VERSION 5.7 ;
BUSBITCHARS "[]" ;
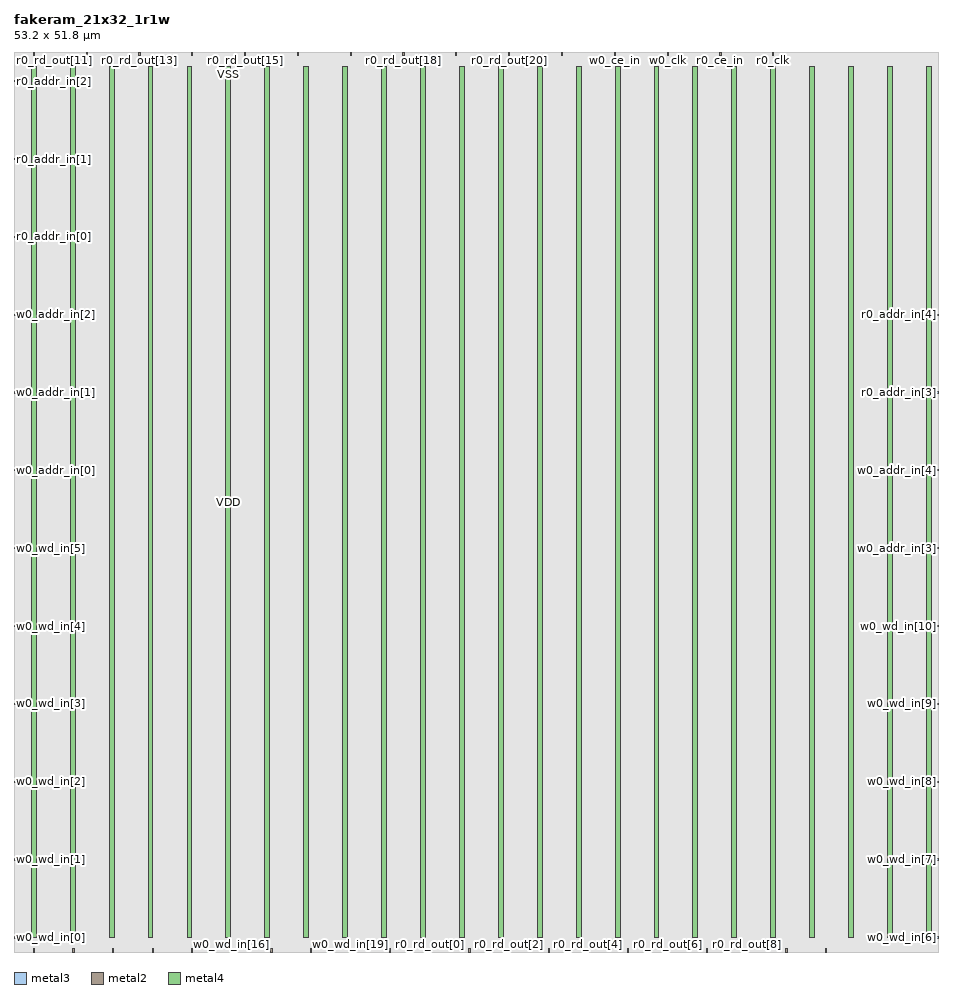
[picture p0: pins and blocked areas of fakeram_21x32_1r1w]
MACRO fakeram_21x32_1r1w
  FOREIGN fakeram_21x32_1r1w 0 0 ;
  SYMMETRY X Y R90 ;
  SIZE 53.200 BY 51.800 ;
  CLASS BLOCK ;
  PIN w0_wd_in[0]
    DIRECTION INPUT ;
    USE SIGNAL ;
    SHAPE ABUTMENT ;
    PORT
      LAYER metal3 ;
      RECT 0.000 0.805 0.210 0.875 ;
    END
  END w0_wd_in[0]
  PIN w0_wd_in[1]
    DIRECTION INPUT ;
    USE SIGNAL ;
    SHAPE ABUTMENT ;
    PORT
      LAYER metal3 ;
      RECT 0.000 5.285 0.210 5.355 ;
    END
  END w0_wd_in[1]
  PIN w0_wd_in[2]
    DIRECTION INPUT ;
    USE SIGNAL ;
    SHAPE ABUTMENT ;
    PORT
      LAYER metal3 ;
      RECT 0.000 9.765 0.210 9.835 ;
    END
  END w0_wd_in[2]
  PIN w0_wd_in[3]
    DIRECTION INPUT ;
    USE SIGNAL ;
    SHAPE ABUTMENT ;
    PORT
      LAYER metal3 ;
      RECT 0.000 14.245 0.210 14.315 ;
    END
  END w0_wd_in[3]
  PIN w0_wd_in[4]
    DIRECTION INPUT ;
    USE SIGNAL ;
    SHAPE ABUTMENT ;
    PORT
      LAYER metal3 ;
      RECT 0.000 18.725 0.210 18.795 ;
    END
  END w0_wd_in[4]
  PIN w0_wd_in[5]
    DIRECTION INPUT ;
    USE SIGNAL ;
    SHAPE ABUTMENT ;
    PORT
      LAYER metal3 ;
      RECT 0.000 23.205 0.210 23.275 ;
    END
  END w0_wd_in[5]
  PIN w0_wd_in[6]
    DIRECTION INPUT ;
    USE SIGNAL ;
    SHAPE ABUTMENT ;
    PORT
      LAYER metal3 ;
      RECT 52.990 0.805 53.200 0.875 ;
    END
  END w0_wd_in[6]
  PIN w0_wd_in[7]
    DIRECTION INPUT ;
    USE SIGNAL ;
    SHAPE ABUTMENT ;
    PORT
      LAYER metal3 ;
      RECT 52.990 5.285 53.200 5.355 ;
    END
  END w0_wd_in[7]
  PIN w0_wd_in[8]
    DIRECTION INPUT ;
    USE SIGNAL ;
    SHAPE ABUTMENT ;
    PORT
      LAYER metal3 ;
      RECT 52.990 9.765 53.200 9.835 ;
    END
  END w0_wd_in[8]
  PIN w0_wd_in[9]
    DIRECTION INPUT ;
    USE SIGNAL ;
    SHAPE ABUTMENT ;
    PORT
      LAYER metal3 ;
      RECT 52.990 14.245 53.200 14.315 ;
    END
  END w0_wd_in[9]
  PIN w0_wd_in[10]
    DIRECTION INPUT ;
    USE SIGNAL ;
    SHAPE ABUTMENT ;
    PORT
      LAYER metal3 ;
      RECT 52.990 18.725 53.200 18.795 ;
    END
  END w0_wd_in[10]
  PIN w0_wd_in[11]
    DIRECTION INPUT ;
    USE SIGNAL ;
    SHAPE ABUTMENT ;
    PORT
      LAYER metal2 ;
      RECT 1.105 0.000 1.175 0.210 ;
    END
  END w0_wd_in[11]
  PIN w0_wd_in[12]
    DIRECTION INPUT ;
    USE SIGNAL ;
    SHAPE ABUTMENT ;
    PORT
      LAYER metal2 ;
      RECT 3.385 0.000 3.455 0.210 ;
    END
  END w0_wd_in[12]
  PIN w0_wd_in[13]
    DIRECTION INPUT ;
    USE SIGNAL ;
    SHAPE ABUTMENT ;
    PORT
      LAYER metal2 ;
      RECT 5.665 0.000 5.735 0.210 ;
    END
  END w0_wd_in[13]
  PIN w0_wd_in[14]
    DIRECTION INPUT ;
    USE SIGNAL ;
    SHAPE ABUTMENT ;
    PORT
      LAYER metal2 ;
      RECT 7.945 0.000 8.015 0.210 ;
    END
  END w0_wd_in[14]
  PIN w0_wd_in[15]
    DIRECTION INPUT ;
    USE SIGNAL ;
    SHAPE ABUTMENT ;
    PORT
      LAYER metal2 ;
      RECT 10.225 0.000 10.295 0.210 ;
    END
  END w0_wd_in[15]
  PIN w0_wd_in[16]
    DIRECTION INPUT ;
    USE SIGNAL ;
    SHAPE ABUTMENT ;
    PORT
      LAYER metal2 ;
      RECT 12.505 0.000 12.575 0.210 ;
    END
  END w0_wd_in[16]
  PIN w0_wd_in[17]
    DIRECTION INPUT ;
    USE SIGNAL ;
    SHAPE ABUTMENT ;
    PORT
      LAYER metal2 ;
      RECT 14.785 0.000 14.855 0.210 ;
    END
  END w0_wd_in[17]
  PIN w0_wd_in[18]
    DIRECTION INPUT ;
    USE SIGNAL ;
    SHAPE ABUTMENT ;
    PORT
      LAYER metal2 ;
      RECT 17.065 0.000 17.135 0.210 ;
    END
  END w0_wd_in[18]
  PIN w0_wd_in[19]
    DIRECTION INPUT ;
    USE SIGNAL ;
    SHAPE ABUTMENT ;
    PORT
      LAYER metal2 ;
      RECT 19.345 0.000 19.415 0.210 ;
    END
  END w0_wd_in[19]
  PIN w0_wd_in[20]
    DIRECTION INPUT ;
    USE SIGNAL ;
    SHAPE ABUTMENT ;
    PORT
      LAYER metal2 ;
      RECT 21.625 0.000 21.695 0.210 ;
    END
  END w0_wd_in[20]
  PIN r0_rd_out[0]
    DIRECTION OUTPUT ;
    USE SIGNAL ;
    SHAPE ABUTMENT ;
    PORT
      LAYER metal2 ;
      RECT 23.905 0.000 23.975 0.210 ;
    END
  END r0_rd_out[0]
  PIN r0_rd_out[1]
    DIRECTION OUTPUT ;
    USE SIGNAL ;
    SHAPE ABUTMENT ;
    PORT
      LAYER metal2 ;
      RECT 26.185 0.000 26.255 0.210 ;
    END
  END r0_rd_out[1]
  PIN r0_rd_out[2]
    DIRECTION OUTPUT ;
    USE SIGNAL ;
    SHAPE ABUTMENT ;
    PORT
      LAYER metal2 ;
      RECT 28.465 0.000 28.535 0.210 ;
    END
  END r0_rd_out[2]
  PIN r0_rd_out[3]
    DIRECTION OUTPUT ;
    USE SIGNAL ;
    SHAPE ABUTMENT ;
    PORT
      LAYER metal2 ;
      RECT 30.745 0.000 30.815 0.210 ;
    END
  END r0_rd_out[3]
  PIN r0_rd_out[4]
    DIRECTION OUTPUT ;
    USE SIGNAL ;
    SHAPE ABUTMENT ;
    PORT
      LAYER metal2 ;
      RECT 33.025 0.000 33.095 0.210 ;
    END
  END r0_rd_out[4]
  PIN r0_rd_out[5]
    DIRECTION OUTPUT ;
    USE SIGNAL ;
    SHAPE ABUTMENT ;
    PORT
      LAYER metal2 ;
      RECT 35.305 0.000 35.375 0.210 ;
    END
  END r0_rd_out[5]
  PIN r0_rd_out[6]
    DIRECTION OUTPUT ;
    USE SIGNAL ;
    SHAPE ABUTMENT ;
    PORT
      LAYER metal2 ;
      RECT 37.585 0.000 37.655 0.210 ;
    END
  END r0_rd_out[6]
  PIN r0_rd_out[7]
    DIRECTION OUTPUT ;
    USE SIGNAL ;
    SHAPE ABUTMENT ;
    PORT
      LAYER metal2 ;
      RECT 39.865 0.000 39.935 0.210 ;
    END
  END r0_rd_out[7]
  PIN r0_rd_out[8]
    DIRECTION OUTPUT ;
    USE SIGNAL ;
    SHAPE ABUTMENT ;
    PORT
      LAYER metal2 ;
      RECT 42.145 0.000 42.215 0.210 ;
    END
  END r0_rd_out[8]
  PIN r0_rd_out[9]
    DIRECTION OUTPUT ;
    USE SIGNAL ;
    SHAPE ABUTMENT ;
    PORT
      LAYER metal2 ;
      RECT 44.425 0.000 44.495 0.210 ;
    END
  END r0_rd_out[9]
  PIN r0_rd_out[10]
    DIRECTION OUTPUT ;
    USE SIGNAL ;
    SHAPE ABUTMENT ;
    PORT
      LAYER metal2 ;
      RECT 46.705 0.000 46.775 0.210 ;
    END
  END r0_rd_out[10]
  PIN r0_rd_out[11]
    DIRECTION OUTPUT ;
    USE SIGNAL ;
    SHAPE ABUTMENT ;
    PORT
      LAYER metal2 ;
      RECT 1.105 51.590 1.175 51.800 ;
    END
  END r0_rd_out[11]
  PIN r0_rd_out[12]
    DIRECTION OUTPUT ;
    USE SIGNAL ;
    SHAPE ABUTMENT ;
    PORT
      LAYER metal2 ;
      RECT 4.145 51.590 4.215 51.800 ;
    END
  END r0_rd_out[12]
  PIN r0_rd_out[13]
    DIRECTION OUTPUT ;
    USE SIGNAL ;
    SHAPE ABUTMENT ;
    PORT
      LAYER metal2 ;
      RECT 7.185 51.590 7.255 51.800 ;
    END
  END r0_rd_out[13]
  PIN r0_rd_out[14]
    DIRECTION OUTPUT ;
    USE SIGNAL ;
    SHAPE ABUTMENT ;
    PORT
      LAYER metal2 ;
      RECT 10.225 51.590 10.295 51.800 ;
    END
  END r0_rd_out[14]
  PIN r0_rd_out[15]
    DIRECTION OUTPUT ;
    USE SIGNAL ;
    SHAPE ABUTMENT ;
    PORT
      LAYER metal2 ;
      RECT 13.265 51.590 13.335 51.800 ;
    END
  END r0_rd_out[15]
  PIN r0_rd_out[16]
    DIRECTION OUTPUT ;
    USE SIGNAL ;
    SHAPE ABUTMENT ;
    PORT
      LAYER metal2 ;
      RECT 16.305 51.590 16.375 51.800 ;
    END
  END r0_rd_out[16]
  PIN r0_rd_out[17]
    DIRECTION OUTPUT ;
    USE SIGNAL ;
    SHAPE ABUTMENT ;
    PORT
      LAYER metal2 ;
      RECT 19.345 51.590 19.415 51.800 ;
    END
  END r0_rd_out[17]
  PIN r0_rd_out[18]
    DIRECTION OUTPUT ;
    USE SIGNAL ;
    SHAPE ABUTMENT ;
    PORT
      LAYER metal2 ;
      RECT 22.385 51.590 22.455 51.800 ;
    END
  END r0_rd_out[18]
  PIN r0_rd_out[19]
    DIRECTION OUTPUT ;
    USE SIGNAL ;
    SHAPE ABUTMENT ;
    PORT
      LAYER metal2 ;
      RECT 25.425 51.590 25.495 51.800 ;
    END
  END r0_rd_out[19]
  PIN r0_rd_out[20]
    DIRECTION OUTPUT ;
    USE SIGNAL ;
    SHAPE ABUTMENT ;
    PORT
      LAYER metal2 ;
      RECT 28.465 51.590 28.535 51.800 ;
    END
  END r0_rd_out[20]
  PIN w0_addr_in[0]
    DIRECTION INPUT ;
    USE SIGNAL ;
    SHAPE ABUTMENT ;
    PORT
      LAYER metal3 ;
      RECT 0.000 27.685 0.210 27.755 ;
    END
  END w0_addr_in[0]
  PIN w0_addr_in[1]
    DIRECTION INPUT ;
    USE SIGNAL ;
    SHAPE ABUTMENT ;
    PORT
      LAYER metal3 ;
      RECT 0.000 32.165 0.210 32.235 ;
    END
  END w0_addr_in[1]
  PIN w0_addr_in[2]
    DIRECTION INPUT ;
    USE SIGNAL ;
    SHAPE ABUTMENT ;
    PORT
      LAYER metal3 ;
      RECT 0.000 36.645 0.210 36.715 ;
    END
  END w0_addr_in[2]
  PIN w0_addr_in[3]
    DIRECTION INPUT ;
    USE SIGNAL ;
    SHAPE ABUTMENT ;
    PORT
      LAYER metal3 ;
      RECT 52.990 23.205 53.200 23.275 ;
    END
  END w0_addr_in[3]
  PIN w0_addr_in[4]
    DIRECTION INPUT ;
    USE SIGNAL ;
    SHAPE ABUTMENT ;
    PORT
      LAYER metal3 ;
      RECT 52.990 27.685 53.200 27.755 ;
    END
  END w0_addr_in[4]
  PIN r0_addr_in[0]
    DIRECTION INPUT ;
    USE SIGNAL ;
    SHAPE ABUTMENT ;
    PORT
      LAYER metal3 ;
      RECT 0.000 41.125 0.210 41.195 ;
    END
  END r0_addr_in[0]
  PIN r0_addr_in[1]
    DIRECTION INPUT ;
    USE SIGNAL ;
    SHAPE ABUTMENT ;
    PORT
      LAYER metal3 ;
      RECT 0.000 45.605 0.210 45.675 ;
    END
  END r0_addr_in[1]
  PIN r0_addr_in[2]
    DIRECTION INPUT ;
    USE SIGNAL ;
    SHAPE ABUTMENT ;
    PORT
      LAYER metal3 ;
      RECT 0.000 50.085 0.210 50.155 ;
    END
  END r0_addr_in[2]
  PIN r0_addr_in[3]
    DIRECTION INPUT ;
    USE SIGNAL ;
    SHAPE ABUTMENT ;
    PORT
      LAYER metal3 ;
      RECT 52.990 32.165 53.200 32.235 ;
    END
  END r0_addr_in[3]
  PIN r0_addr_in[4]
    DIRECTION INPUT ;
    USE SIGNAL ;
    SHAPE ABUTMENT ;
    PORT
      LAYER metal3 ;
      RECT 52.990 36.645 53.200 36.715 ;
    END
  END r0_addr_in[4]
  PIN w0_we_in
    DIRECTION INPUT ;
    USE SIGNAL ;
    SHAPE ABUTMENT ;
    PORT
      LAYER metal2 ;
      RECT 31.505 51.590 31.575 51.800 ;
    END
  END w0_we_in
  PIN w0_ce_in
    DIRECTION INPUT ;
    USE SIGNAL ;
    SHAPE ABUTMENT ;
    PORT
      LAYER metal2 ;
      RECT 34.545 51.590 34.615 51.800 ;
    END
  END w0_ce_in
  PIN w0_clk
    DIRECTION INPUT ;
    USE SIGNAL ;
    SHAPE ABUTMENT ;
    PORT
      LAYER metal2 ;
      RECT 37.585 51.590 37.655 51.800 ;
    END
  END w0_clk
  PIN r0_ce_in
    DIRECTION INPUT ;
    USE SIGNAL ;
    SHAPE ABUTMENT ;
    PORT
      LAYER metal2 ;
      RECT 40.625 51.590 40.695 51.800 ;
    END
  END r0_ce_in
  PIN r0_clk
    DIRECTION INPUT ;
    USE SIGNAL ;
    SHAPE ABUTMENT ;
    PORT
      LAYER metal2 ;
      RECT 43.665 51.590 43.735 51.800 ;
    END
  END r0_clk
  PIN VSS
    DIRECTION INOUT ;
    USE GROUND ;
    PORT
      LAYER metal4 ;
      RECT 1.000 0.840 1.280 50.960 ;
      RECT 3.240 0.840 3.520 50.960 ;
      RECT 5.480 0.840 5.760 50.960 ;
      RECT 7.720 0.840 8.000 50.960 ;
      RECT 9.960 0.840 10.240 50.960 ;
      RECT 12.200 0.840 12.480 50.960 ;
      RECT 14.440 0.840 14.720 50.960 ;
      RECT 16.680 0.840 16.960 50.960 ;
      RECT 18.920 0.840 19.200 50.960 ;
      RECT 21.160 0.840 21.440 50.960 ;
      RECT 23.400 0.840 23.680 50.960 ;
      RECT 25.640 0.840 25.920 50.960 ;
      RECT 27.880 0.840 28.160 50.960 ;
      RECT 30.120 0.840 30.400 50.960 ;
      RECT 32.360 0.840 32.640 50.960 ;
      RECT 34.600 0.840 34.880 50.960 ;
      RECT 36.840 0.840 37.120 50.960 ;
      RECT 39.080 0.840 39.360 50.960 ;
      RECT 41.320 0.840 41.600 50.960 ;
      RECT 43.560 0.840 43.840 50.960 ;
      RECT 45.800 0.840 46.080 50.960 ;
      RECT 48.040 0.840 48.320 50.960 ;
      RECT 50.280 0.840 50.560 50.960 ;
      RECT 52.520 0.840 52.800 50.960 ;
    END
  END VSS
  PIN VDD
    DIRECTION INOUT ;
    USE POWER ;
    PORT
      LAYER metal4 ;
      RECT 1.000 0.840 1.280 50.960 ;
      RECT 3.240 0.840 3.520 50.960 ;
      RECT 5.480 0.840 5.760 50.960 ;
      RECT 7.720 0.840 8.000 50.960 ;
      RECT 9.960 0.840 10.240 50.960 ;
      RECT 12.200 0.840 12.480 50.960 ;
      RECT 14.440 0.840 14.720 50.960 ;
      RECT 16.680 0.840 16.960 50.960 ;
      RECT 18.920 0.840 19.200 50.960 ;
      RECT 21.160 0.840 21.440 50.960 ;
      RECT 23.400 0.840 23.680 50.960 ;
      RECT 25.640 0.840 25.920 50.960 ;
      RECT 27.880 0.840 28.160 50.960 ;
      RECT 30.120 0.840 30.400 50.960 ;
      RECT 32.360 0.840 32.640 50.960 ;
      RECT 34.600 0.840 34.880 50.960 ;
      RECT 36.840 0.840 37.120 50.960 ;
      RECT 39.080 0.840 39.360 50.960 ;
      RECT 41.320 0.840 41.600 50.960 ;
      RECT 43.560 0.840 43.840 50.960 ;
      RECT 45.800 0.840 46.080 50.960 ;
      RECT 48.040 0.840 48.320 50.960 ;
      RECT 50.280 0.840 50.560 50.960 ;
      RECT 52.520 0.840 52.800 50.960 ;
    END
  END VDD
  OBS
    LAYER metal1 ;
    RECT 0 0 53.200 51.800 ;
    LAYER metal2 ;
    RECT 0 0 53.200 51.800 ;
    LAYER metal3 ;
    RECT 0 0 53.200 51.800 ;
    LAYER metal4 ;
    RECT 0 0 53.200 51.800 ;
    LAYER OVERLAP ;
    RECT 0 0 53.200 51.800 ;
  END
END fakeram_21x32_1r1w

END LIBRARY
